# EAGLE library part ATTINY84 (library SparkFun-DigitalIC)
Atmel 14-pin 2/4/8kB flash uC

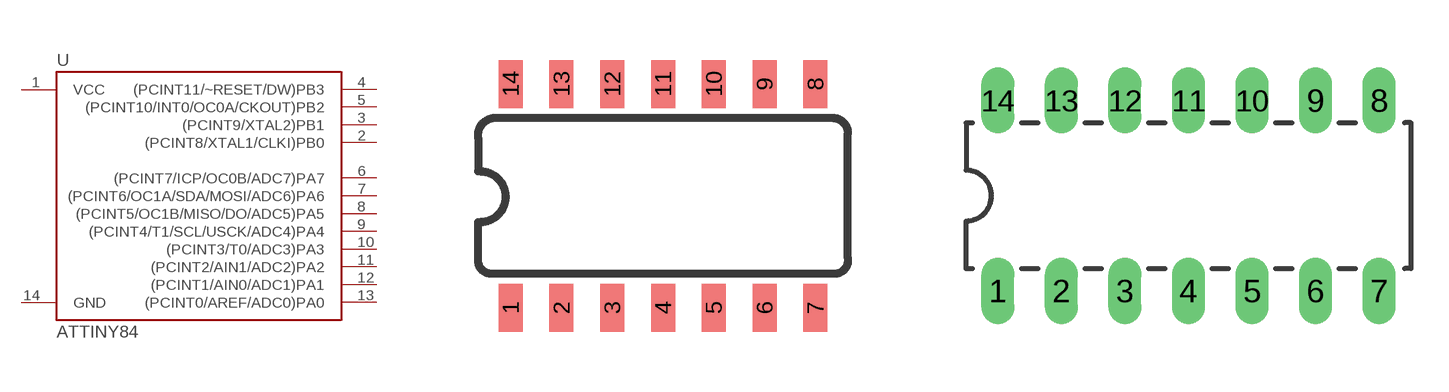
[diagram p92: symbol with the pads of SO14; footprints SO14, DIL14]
Designator prefix -

## ATTINY84 (PROD_ID: IC-11285)  [SO14]
1  VCC
2  (PCINT8/XTAL1/CLKI)PB0
3  (PCINT9/XTAL2)PB1
4  (PCINT11/~RESET/DW)PB3
5  (PCINT10/INT0/OC0A/CKOUT)PB2
6  (PCINT7/ICP/OC0B/ADC7)PA7
7  (PCINT6/OC1A/SDA/MOSI/ADC6)PA6
8  (PCINT5/OC1B/MISO/DO/ADC5)PA5
9  (PCINT4/T1/SCL/USCK/ADC4)PA4
10  (PCINT3/T0/ADC3)PA3
11  (PCINT2/AIN1/ADC2)PA2
12  (PCINT1/AIN0/ADC1)PA1
13  (PCINT0/AREF/ADC0)PA0
14  GND

## ATTINY84ATTINY84-20PU  [DIL14]
Pads as for SO14

## ATTINY84ATTINY84-20MU  [QFN20]
1  (PCINT4/T1/SCL/USCK/ADC4)PA4
2  (PCINT3/T0/ADC3)PA3
3  (PCINT2/AIN1/ADC2)PA2
4  (PCINT1/AIN0/ADC1)PA1
5  (PCINT0/AREF/ADC0)PA0
8  GND
9  VCC
11  (PCINT8/XTAL1/CLKI)PB0
12  (PCINT9/XTAL2)PB1
13  (PCINT11/~RESET/DW)PB3
14  (PCINT10/INT0/OC0A/CKOUT)PB2
15  (PCINT7/ICP/OC0B/ADC7)PA7
16  (PCINT6/OC1A/SDA/MOSI/ADC6)PA6
20  (PCINT5/OC1B/MISO/DO/ADC5)PA5

## Footprint SO14 (pad centres in mm)
smd 0.6 x 1.2: 1 -3.81,-2.8; 2 -2.54,-2.8; 3 -1.27,-2.8; 4 0,-2.8; 5 1.27,-2.8; 6 2.54,-2.8; 7 3.81,-2.8; 8 3.81,2.8; 9 2.54,2.8; 10 1.27,2.8; 11 0,2.8; 12 -1.27,2.8; 13 -2.54,2.8; 14 -3.81,2.8

## Footprint DIL14 (pad centres in mm)
drill 0.813 long: 1 -8.89,-3.81; 2 -6.35,-3.81; 3 -3.81,-3.81; 4 -1.27,-3.81; 5 1.27,-3.81; 6 3.81,-3.81; 7 6.35,-3.81; 8 6.35,3.81; 9 3.81,3.81; 10 1.27,3.81; 11 -1.27,3.81; 12 -3.81,3.81; 13 -6.35,3.81; 14 -8.89,3.81

## Footprint QFN20 (pad centres in mm)
smd 1 x 1: 0 0,0
smd 0.65 x 0.3: 1 -1.9,1; 2 -1.9,0.5; 3 -1.9,0; 4 -1.9,-0.5; 5 -1.9,-1; 11 1.9,-1; 12 1.9,-0.5; 13 1.9,0; 14 1.9,0.5; 15 1.9,1
smd 0.3 x 0.65: 6 -1,-1.9; 7 -0.5,-1.9; 8 0,-1.9; 9 0.5,-1.9; 10 1,-1.9; 16 1,1.9; 17 0.5,1.9; 18 0,1.9; 19 -0.5,1.9; 20 -1,1.9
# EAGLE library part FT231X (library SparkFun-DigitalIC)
FTDI FT231X Full Speed USB to Full-handshake UART This USB2.0 Full Speed IC offers a compact bridge to full handshake UART interfaces. The device is a UART, capable of operating up to 3MBaud, with low power consumption (8mA). The FT231X includes the complete FT-X series feature set and enables USB to be added into a system design quickly and easily over a UART interface.

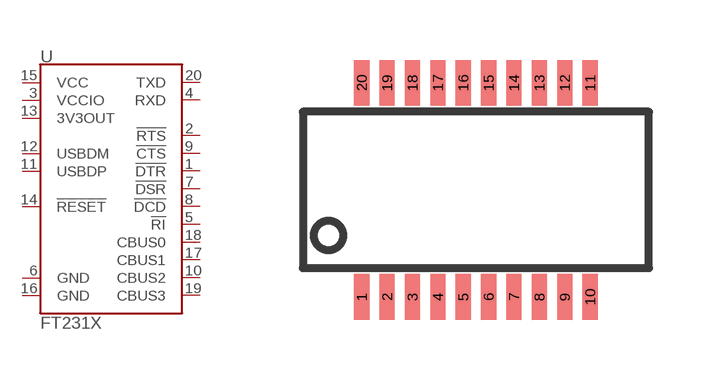
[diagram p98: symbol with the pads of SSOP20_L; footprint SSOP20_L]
Designator prefix U

## FT231XS (PROD_ID: IC-11524; VALUE: FTS31XS-U)  [SSOP20_L]
1  !DTR
2  !RTS
3  VCCIO
4  RXD
5  !RI
6  GND
7  !DSR
8  !DCD
9  !CTS
10  CBUS2
11  USBDP
12  USBDM
13  3V3OUT
14  !RESET
15  VCC
16  GND
17  CBUS1
18  CBUS0
19  CBUS3
20  TXD

## Footprint SSOP20_L (pad centres in mm)
Longer version of SSOP-20 Package
smd 0.381 x 1.143: 1 -2.857,-2.68; 2 -2.223,-2.68; 3 -1.587,-2.68; 4 -0.953,-2.68; 5 -0.318,-2.68; 6 0.318,-2.68; 7 0.953,-2.68; 8 1.587,-2.68; 9 2.223,-2.68; 10 2.857,-2.68; 11 2.857,2.68; 12 2.223,2.68; 13 1.587,2.68; 14 0.953,2.68; 15 0.318,2.68; 16 -0.318,2.68; 17 -0.953,2.68; 18 -1.587,2.68; 19 -2.223,2.68; 20 -2.857,2.68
